VERSION 5.4 ;
NAMESCASESENSITIVE ON ;
BUSBITCHARS "[]" ;
DIVIDERCHAR "/" ;
UNITS
  DATABASE MICRONS 1000 ;
END UNITS
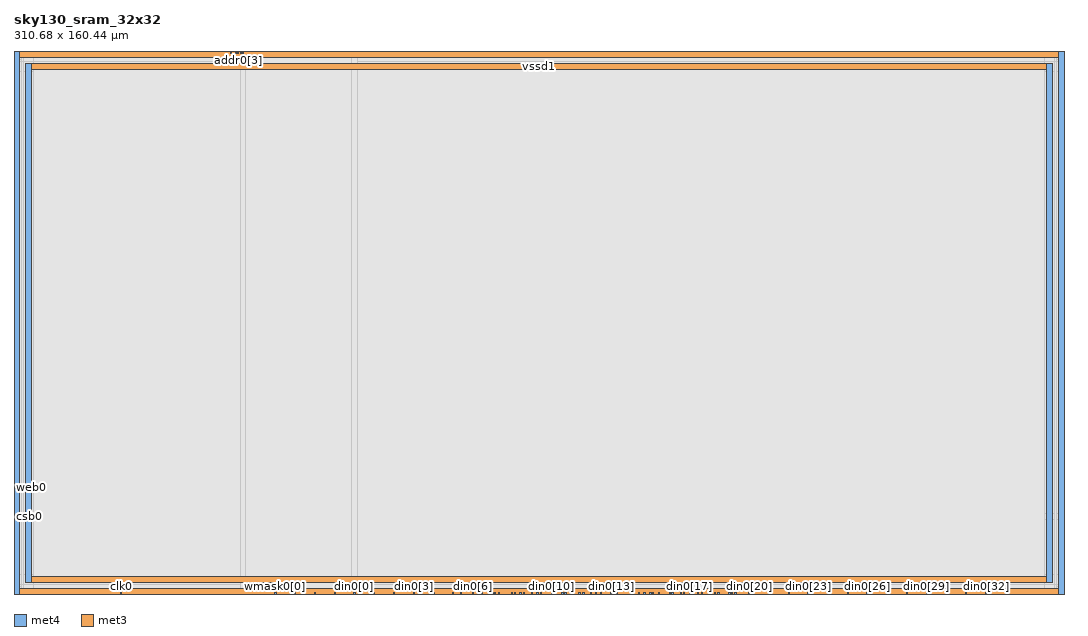
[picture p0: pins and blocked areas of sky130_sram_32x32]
MACRO sky130_sram_32x32
   CLASS BLOCK ;
   SIZE 310.68 BY 160.44 ;
   SYMMETRY X Y R90 ;
   PIN din0[0]
      DIRECTION INPUT ;
      PORT
         LAYER met4 ;
         RECT  100.54 0.0 100.92 0.38 ;
      END
   END din0[0]
   PIN din0[1]
      DIRECTION INPUT ;
      PORT
         LAYER met4 ;
         RECT  106.38 0.0 106.76 0.38 ;
      END
   END din0[1]
   PIN din0[2]
      DIRECTION INPUT ;
      PORT
         LAYER met4 ;
         RECT  112.22 0.0 112.6 0.38 ;
      END
   END din0[2]
   PIN din0[3]
      DIRECTION INPUT ;
      PORT
         LAYER met4 ;
         RECT  118.06 0.0 118.44 0.38 ;
      END
   END din0[3]
   PIN din0[4]
      DIRECTION INPUT ;
      PORT
         LAYER met4 ;
         RECT  123.9 0.0 124.28 0.38 ;
      END
   END din0[4]
   PIN din0[5]
      DIRECTION INPUT ;
      PORT
         LAYER met4 ;
         RECT  129.74 0.0 130.12 0.38 ;
      END
   END din0[5]
   PIN din0[6]
      DIRECTION INPUT ;
      PORT
         LAYER met4 ;
         RECT  135.58 0.0 135.96 0.38 ;
      END
   END din0[6]
   PIN din0[7]
      DIRECTION INPUT ;
      PORT
         LAYER met4 ;
         RECT  141.42 0.0 141.8 0.38 ;
      END
   END din0[7]
   PIN din0[8]
      DIRECTION INPUT ;
      PORT
         LAYER met4 ;
         RECT  147.26 0.0 147.64 0.38 ;
      END
   END din0[8]
   PIN din0[9]
      DIRECTION INPUT ;
      PORT
         LAYER met4 ;
         RECT  153.1 0.0 153.48 0.38 ;
      END
   END din0[9]
   PIN din0[10]
      DIRECTION INPUT ;
      PORT
         LAYER met4 ;
         RECT  158.94 0.0 159.32 0.38 ;
      END
   END din0[10]
   PIN din0[11]
      DIRECTION INPUT ;
      PORT
         LAYER met4 ;
         RECT  164.78 0.0 165.16 0.38 ;
      END
   END din0[11]
   PIN din0[12]
      DIRECTION INPUT ;
      PORT
         LAYER met4 ;
         RECT  170.62 0.0 171.0 0.38 ;
      END
   END din0[12]
   PIN din0[13]
      DIRECTION INPUT ;
      PORT
         LAYER met4 ;
         RECT  176.46 0.0 176.84 0.38 ;
      END
   END din0[13]
   PIN din0[14]
      DIRECTION INPUT ;
      PORT
         LAYER met4 ;
         RECT  182.3 0.0 182.68 0.38 ;
      END
   END din0[14]
   PIN din0[15]
      DIRECTION INPUT ;
      PORT
         LAYER met4 ;
         RECT  188.14 0.0 188.52 0.38 ;
      END
   END din0[15]
   PIN din0[16]
      DIRECTION INPUT ;
      PORT
         LAYER met4 ;
         RECT  193.98 0.0 194.36 0.38 ;
      END
   END din0[16]
   PIN din0[17]
      DIRECTION INPUT ;
      PORT
         LAYER met4 ;
         RECT  199.82 0.0 200.2 0.38 ;
      END
   END din0[17]
   PIN din0[18]
      DIRECTION INPUT ;
      PORT
         LAYER met4 ;
         RECT  205.66 0.0 206.04 0.38 ;
      END
   END din0[18]
   PIN din0[19]
      DIRECTION INPUT ;
      PORT
         LAYER met4 ;
         RECT  211.5 0.0 211.88 0.38 ;
      END
   END din0[19]
   PIN din0[20]
      DIRECTION INPUT ;
      PORT
         LAYER met4 ;
         RECT  217.34 0.0 217.72 0.38 ;
      END
   END din0[20]
   PIN din0[21]
      DIRECTION INPUT ;
      PORT
         LAYER met4 ;
         RECT  223.18 0.0 223.56 0.38 ;
      END
   END din0[21]
   PIN din0[22]
      DIRECTION INPUT ;
      PORT
         LAYER met4 ;
         RECT  229.02 0.0 229.4 0.38 ;
      END
   END din0[22]
   PIN din0[23]
      DIRECTION INPUT ;
      PORT
         LAYER met4 ;
         RECT  234.86 0.0 235.24 0.38 ;
      END
   END din0[23]
   PIN din0[24]
      DIRECTION INPUT ;
      PORT
         LAYER met4 ;
         RECT  240.7 0.0 241.08 0.38 ;
      END
   END din0[24]
   PIN din0[25]
      DIRECTION INPUT ;
      PORT
         LAYER met4 ;
         RECT  246.54 0.0 246.92 0.38 ;
      END
   END din0[25]
   PIN din0[26]
      DIRECTION INPUT ;
      PORT
         LAYER met4 ;
         RECT  252.38 0.0 252.76 0.38 ;
      END
   END din0[26]
   PIN din0[27]
      DIRECTION INPUT ;
      PORT
         LAYER met4 ;
         RECT  258.22 0.0 258.6 0.38 ;
      END
   END din0[27]
   PIN din0[28]
      DIRECTION INPUT ;
      PORT
         LAYER met4 ;
         RECT  264.06 0.0 264.44 0.38 ;
      END
   END din0[28]
   PIN din0[29]
      DIRECTION INPUT ;
      PORT
         LAYER met4 ;
         RECT  269.9 0.0 270.28 0.38 ;
      END
   END din0[29]
   PIN din0[30]
      DIRECTION INPUT ;
      PORT
         LAYER met4 ;
         RECT  275.74 0.0 276.12 0.38 ;
      END
   END din0[30]
   PIN din0[31]
      DIRECTION INPUT ;
      PORT
         LAYER met4 ;
         RECT  281.58 0.0 281.96 0.38 ;
      END
   END din0[31]
   PIN din0[32]
      DIRECTION INPUT ;
      PORT
         LAYER met4 ;
         RECT  287.42 0.0 287.8 0.38 ;
      END
   END din0[32]
   PIN addr0[0]
      DIRECTION INPUT ;
      PORT
         LAYER met4 ;
         RECT  67.57 160.06 67.95 160.44 ;
      END
   END addr0[0]
   PIN addr0[1]
      DIRECTION INPUT ;
      PORT
         LAYER met4 ;
         RECT  63.96 160.06 64.34 160.44 ;
      END
   END addr0[1]
   PIN addr0[2]
      DIRECTION INPUT ;
      PORT
         LAYER met4 ;
         RECT  66.88 160.06 67.26 160.44 ;
      END
   END addr0[2]
   PIN addr0[3]
      DIRECTION INPUT ;
      PORT
         LAYER met4 ;
         RECT  66.19 160.06 66.57 160.44 ;
      END
   END addr0[3]
   PIN addr0[4]
      DIRECTION INPUT ;
      PORT
         LAYER met4 ;
         RECT  65.5 160.06 65.88 160.44 ;
      END
   END addr0[4]
   PIN csb0
      DIRECTION INPUT ;
      PORT
         LAYER met3 ;
         RECT  0.0 22.77 0.38 23.15 ;
      END
   END csb0
   PIN web0
      DIRECTION INPUT ;
      PORT
         LAYER met3 ;
         RECT  0.0 31.27 0.38 31.65 ;
      END
   END web0
   PIN clk0
      DIRECTION INPUT ;
      PORT
         LAYER met4 ;
         RECT  31.505 0.0 31.885 0.38 ;
      END
   END clk0
   PIN wmask0[0]
      DIRECTION INPUT ;
      PORT
         LAYER met4 ;
         RECT  77.18 0.0 77.56 0.38 ;
      END
   END wmask0[0]
   PIN wmask0[1]
      DIRECTION INPUT ;
      PORT
         LAYER met4 ;
         RECT  83.02 0.0 83.4 0.38 ;
      END
   END wmask0[1]
   PIN wmask0[2]
      DIRECTION INPUT ;
      PORT
         LAYER met4 ;
         RECT  88.86 0.0 89.24 0.38 ;
      END
   END wmask0[2]
   PIN wmask0[3]
      DIRECTION INPUT ;
      PORT
         LAYER met4 ;
         RECT  94.7 0.0 95.08 0.38 ;
      END
   END wmask0[3]
   PIN spare_wen0
      DIRECTION INPUT ;
      PORT
         LAYER met4 ;
         RECT  293.26 0.0 293.64 0.38 ;
      END
   END spare_wen0
   PIN dout0[0]
      DIRECTION OUTPUT ;
      PORT
         LAYER met4 ;
         RECT  132.025 0.0 132.405 0.38 ;
      END
   END dout0[0]
   PIN dout0[1]
      DIRECTION OUTPUT ;
      PORT
         LAYER met4 ;
         RECT  137.14 0.0 137.52 0.38 ;
      END
   END dout0[1]
   PIN dout0[2]
      DIRECTION OUTPUT ;
      PORT
         LAYER met4 ;
         RECT  138.29 0.0 138.67 0.38 ;
      END
   END dout0[2]
   PIN dout0[3]
      DIRECTION OUTPUT ;
      PORT
         LAYER met4 ;
         RECT  142.14 0.0 142.52 0.38 ;
      END
   END dout0[3]
   PIN dout0[4]
      DIRECTION OUTPUT ;
      PORT
         LAYER met4 ;
         RECT  143.29 0.0 143.67 0.38 ;
      END
   END dout0[4]
   PIN dout0[5]
      DIRECTION OUTPUT ;
      PORT
         LAYER met4 ;
         RECT  147.95 0.0 148.33 0.38 ;
      END
   END dout0[5]
   PIN dout0[6]
      DIRECTION OUTPUT ;
      PORT
         LAYER met4 ;
         RECT  149.67 0.0 150.05 0.38 ;
      END
   END dout0[6]
   PIN dout0[7]
      DIRECTION OUTPUT ;
      PORT
         LAYER met4 ;
         RECT  150.76 0.0 151.14 0.38 ;
      END
   END dout0[7]
   PIN dout0[8]
      DIRECTION OUTPUT ;
      PORT
         LAYER met4 ;
         RECT  154.67 0.0 155.05 0.38 ;
      END
   END dout0[8]
   PIN dout0[9]
      DIRECTION OUTPUT ;
      PORT
         LAYER met4 ;
         RECT  155.76 0.0 156.14 0.38 ;
      END
   END dout0[9]
   PIN dout0[10]
      DIRECTION OUTPUT ;
      PORT
         LAYER met4 ;
         RECT  159.67 0.0 160.05 0.38 ;
      END
   END dout0[10]
   PIN dout0[11]
      DIRECTION OUTPUT ;
      PORT
         LAYER met4 ;
         RECT  162.14 0.0 162.52 0.38 ;
      END
   END dout0[11]
   PIN dout0[12]
      DIRECTION OUTPUT ;
      PORT
         LAYER met4 ;
         RECT  162.975 0.0 163.355 0.38 ;
      END
   END dout0[12]
   PIN dout0[13]
      DIRECTION OUTPUT ;
      PORT
         LAYER met4 ;
         RECT  167.14 0.0 167.52 0.38 ;
      END
   END dout0[13]
   PIN dout0[14]
      DIRECTION OUTPUT ;
      PORT
         LAYER met4 ;
         RECT  168.29 0.0 168.67 0.38 ;
      END
   END dout0[14]
   PIN dout0[15]
      DIRECTION OUTPUT ;
      PORT
         LAYER met4 ;
         RECT  172.08 0.0 172.46 0.38 ;
      END
   END dout0[15]
   PIN dout0[16]
      DIRECTION OUTPUT ;
      PORT
         LAYER met4 ;
         RECT  173.545 0.0 173.925 0.38 ;
      END
   END dout0[16]
   PIN dout0[17]
      DIRECTION OUTPUT ;
      PORT
         LAYER met4 ;
         RECT  177.15 0.0 177.53 0.38 ;
      END
   END dout0[17]
   PIN dout0[18]
      DIRECTION OUTPUT ;
      PORT
         LAYER met4 ;
         RECT  178.29 0.0 178.67 0.38 ;
      END
   END dout0[18]
   PIN dout0[19]
      DIRECTION OUTPUT ;
      PORT
         LAYER met4 ;
         RECT  182.99 0.0 183.37 0.38 ;
      END
   END dout0[19]
   PIN dout0[20]
      DIRECTION OUTPUT ;
      PORT
         LAYER met4 ;
         RECT  184.67 0.0 185.05 0.38 ;
      END
   END dout0[20]
   PIN dout0[21]
      DIRECTION OUTPUT ;
      PORT
         LAYER met4 ;
         RECT  186.335 0.0 186.715 0.38 ;
      END
   END dout0[21]
   PIN dout0[22]
      DIRECTION OUTPUT ;
      PORT
         LAYER met4 ;
         RECT  188.83 0.0 189.21 0.38 ;
      END
   END dout0[22]
   PIN dout0[23]
      DIRECTION OUTPUT ;
      PORT
         LAYER met4 ;
         RECT  190.76 0.0 191.14 0.38 ;
      END
   END dout0[23]
   PIN dout0[24]
      DIRECTION OUTPUT ;
      PORT
         LAYER met4 ;
         RECT  194.67 0.0 195.05 0.38 ;
      END
   END dout0[24]
   PIN dout0[25]
      DIRECTION OUTPUT ;
      PORT
         LAYER met4 ;
         RECT  197.14 0.0 197.52 0.38 ;
      END
   END dout0[25]
   PIN dout0[26]
      DIRECTION OUTPUT ;
      PORT
         LAYER met4 ;
         RECT  198.015 0.0 198.395 0.38 ;
      END
   END dout0[26]
   PIN dout0[27]
      DIRECTION OUTPUT ;
      PORT
         LAYER met4 ;
         RECT  202.14 0.0 202.52 0.38 ;
      END
   END dout0[27]
   PIN dout0[28]
      DIRECTION OUTPUT ;
      PORT
         LAYER met4 ;
         RECT  203.29 0.0 203.67 0.38 ;
      END
   END dout0[28]
   PIN dout0[29]
      DIRECTION OUTPUT ;
      PORT
         LAYER met4 ;
         RECT  207.14 0.0 207.52 0.38 ;
      END
   END dout0[29]
   PIN dout0[30]
      DIRECTION OUTPUT ;
      PORT
         LAYER met4 ;
         RECT  208.29 0.0 208.67 0.38 ;
      END
   END dout0[30]
   PIN dout0[31]
      DIRECTION OUTPUT ;
      PORT
         LAYER met4 ;
         RECT  212.19 0.0 212.57 0.38 ;
      END
   END dout0[31]
   PIN dout0[32]
      DIRECTION OUTPUT ;
      PORT
         LAYER met4 ;
         RECT  213.29 0.0 213.67 0.38 ;
      END
   END dout0[32]
   PIN vccd1
      DIRECTION INOUT ;
      USE POWER ; 
      SHAPE ABUTMENT ; 
      PORT
         LAYER met4 ;
         RECT  308.94 0.0 310.68 160.44 ;
         LAYER met3 ;
         RECT  0.0 0.0 310.68 1.74 ;
         LAYER met4 ;
         RECT  0.0 0.0 1.74 160.44 ;
         LAYER met3 ;
         RECT  0.0 158.7 310.68 160.44 ;
      END
   END vccd1
   PIN vssd1
      DIRECTION INOUT ;
      USE GROUND ; 
      SHAPE ABUTMENT ; 
      PORT
         LAYER met3 ;
         RECT  3.48 3.48 307.2 5.22 ;
         LAYER met3 ;
         RECT  3.48 155.22 307.2 156.96 ;
         LAYER met4 ;
         RECT  305.46 3.48 307.2 156.96 ;
         LAYER met4 ;
         RECT  3.48 3.48 5.22 156.96 ;
      END
   END vssd1
   OBS
   LAYER  met1 ;
      RECT  0.62 0.62 310.06 159.82 ;
   LAYER  met2 ;
      RECT  0.62 0.62 310.06 159.82 ;
   LAYER  met3 ;
      RECT  0.98 22.17 310.06 23.75 ;
      RECT  0.62 23.75 0.98 30.67 ;
      RECT  0.62 2.34 0.98 22.17 ;
      RECT  0.62 32.25 0.98 158.1 ;
      RECT  0.98 2.34 2.88 2.88 ;
      RECT  0.98 2.88 2.88 5.82 ;
      RECT  0.98 5.82 2.88 22.17 ;
      RECT  2.88 2.34 307.8 2.88 ;
      RECT  2.88 5.82 307.8 22.17 ;
      RECT  307.8 2.34 310.06 2.88 ;
      RECT  307.8 2.88 310.06 5.82 ;
      RECT  307.8 5.82 310.06 22.17 ;
      RECT  0.98 23.75 2.88 154.62 ;
      RECT  0.98 154.62 2.88 157.56 ;
      RECT  0.98 157.56 2.88 158.1 ;
      RECT  2.88 23.75 307.8 154.62 ;
      RECT  2.88 157.56 307.8 158.1 ;
      RECT  307.8 23.75 310.06 154.62 ;
      RECT  307.8 154.62 310.06 157.56 ;
      RECT  307.8 157.56 310.06 158.1 ;
   LAYER  met4 ;
      RECT  99.94 0.98 101.52 159.82 ;
      RECT  101.52 0.62 105.78 0.98 ;
      RECT  107.36 0.62 111.62 0.98 ;
      RECT  113.2 0.62 117.46 0.98 ;
      RECT  119.04 0.62 123.3 0.98 ;
      RECT  124.88 0.62 129.14 0.98 ;
      RECT  218.32 0.62 222.58 0.98 ;
      RECT  224.16 0.62 228.42 0.98 ;
      RECT  230.0 0.62 234.26 0.98 ;
      RECT  235.84 0.62 240.1 0.98 ;
      RECT  241.68 0.62 245.94 0.98 ;
      RECT  247.52 0.62 251.78 0.98 ;
      RECT  253.36 0.62 257.62 0.98 ;
      RECT  259.2 0.62 263.46 0.98 ;
      RECT  265.04 0.62 269.3 0.98 ;
      RECT  270.88 0.62 275.14 0.98 ;
      RECT  276.72 0.62 280.98 0.98 ;
      RECT  282.56 0.62 286.82 0.98 ;
      RECT  66.97 0.98 68.55 159.46 ;
      RECT  68.55 0.98 99.94 159.46 ;
      RECT  68.55 159.46 99.94 159.82 ;
      RECT  32.485 0.62 76.58 0.98 ;
      RECT  78.16 0.62 82.42 0.98 ;
      RECT  84.0 0.62 88.26 0.98 ;
      RECT  89.84 0.62 94.1 0.98 ;
      RECT  95.68 0.62 99.94 0.98 ;
      RECT  288.4 0.62 292.66 0.98 ;
      RECT  130.72 0.62 131.425 0.98 ;
      RECT  133.005 0.62 134.98 0.98 ;
      RECT  139.27 0.62 140.82 0.98 ;
      RECT  144.27 0.62 146.66 0.98 ;
      RECT  148.93 0.62 149.07 0.98 ;
      RECT  151.74 0.62 152.5 0.98 ;
      RECT  156.74 0.62 158.34 0.98 ;
      RECT  160.65 0.62 161.54 0.98 ;
      RECT  163.955 0.62 164.18 0.98 ;
      RECT  165.76 0.62 166.54 0.98 ;
      RECT  169.27 0.62 170.02 0.98 ;
      RECT  174.525 0.62 175.86 0.98 ;
      RECT  179.27 0.62 181.7 0.98 ;
      RECT  183.97 0.62 184.07 0.98 ;
      RECT  185.65 0.62 185.735 0.98 ;
      RECT  187.315 0.62 187.54 0.98 ;
      RECT  189.81 0.62 190.16 0.98 ;
      RECT  191.74 0.62 193.38 0.98 ;
      RECT  195.65 0.62 196.54 0.98 ;
      RECT  198.995 0.62 199.22 0.98 ;
      RECT  200.8 0.62 201.54 0.98 ;
      RECT  204.27 0.62 205.06 0.98 ;
      RECT  209.27 0.62 210.9 0.98 ;
      RECT  214.27 0.62 216.74 0.98 ;
      RECT  294.24 0.62 308.34 0.98 ;
      RECT  2.34 159.46 63.36 159.82 ;
      RECT  2.34 0.62 30.905 0.98 ;
      RECT  101.52 0.98 304.86 2.88 ;
      RECT  101.52 2.88 304.86 157.56 ;
      RECT  101.52 157.56 304.86 159.82 ;
      RECT  304.86 0.98 307.8 2.88 ;
      RECT  304.86 157.56 307.8 159.82 ;
      RECT  307.8 0.98 308.34 2.88 ;
      RECT  307.8 2.88 308.34 157.56 ;
      RECT  307.8 157.56 308.34 159.82 ;
      RECT  2.34 0.98 2.88 2.88 ;
      RECT  2.34 2.88 2.88 157.56 ;
      RECT  2.34 157.56 2.88 159.46 ;
      RECT  2.88 0.98 5.82 2.88 ;
      RECT  2.88 157.56 5.82 159.46 ;
      RECT  5.82 0.98 66.97 2.88 ;
      RECT  5.82 2.88 66.97 157.56 ;
      RECT  5.82 157.56 66.97 159.46 ;
   END
END    sky130_sram_32x32
END    LIBRARY
